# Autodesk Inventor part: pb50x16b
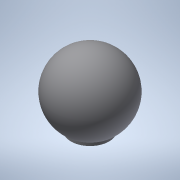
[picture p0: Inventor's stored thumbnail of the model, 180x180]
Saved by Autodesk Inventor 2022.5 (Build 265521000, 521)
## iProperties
Created: 2016-12
Part Number: pb50x16b
Material: 一般
Document SubType Name: Modeling
Designer: imaocorp
Density: 1 g/cm^3
Appearance: 既定
Author: imaocorp
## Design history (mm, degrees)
node "pb50x16b.x_t1"
node "pb50x16b"
node "Base1"
